VERSION 5.7 ;
  NOWIREEXTENSIONATPIN ON ;
  DIVIDERCHAR "/" ;
  BUSBITCHARS "[]" ;
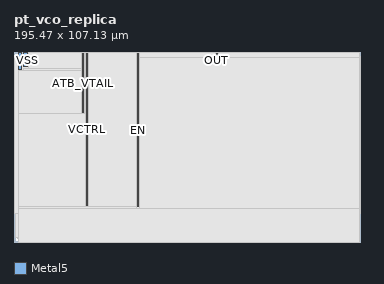
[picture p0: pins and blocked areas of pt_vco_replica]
MACRO pt_vco_replica
  CLASS BLOCK ;
  FOREIGN pt_vco_replica ;
  ORIGIN -1.500 0.000 ;
  SIZE 195.470 BY 107.130 ;
  PIN EN
    ANTENNAGATEAREA 2.240000 ;
    PORT
      LAYER Metal5 ;
        RECT 71.180 19.760 71.620 106.350 ;
    END
  END EN
  PIN VCTRL
    ANTENNAGATEAREA 65.000000 ;
    ANTENNADIFFAREA 0.440000 ;
    PORT
      LAYER Metal5 ;
        RECT 42.380 20.480 42.820 106.350 ;
    END
  END VCTRL
  PIN OUT
    ANTENNADIFFAREA 2.640000 ;
    PORT
      LAYER Metal5 ;
        RECT 115.580 104.750 116.020 106.350 ;
    END
  END OUT
  PIN ATB_VTAIL
    ANTENNADIFFAREA 46.799999 ;
    PORT
      LAYER Metal5 ;
        RECT 39.980 72.800 40.420 106.350 ;
    END
  END ATB_VTAIL
  PIN VDD
    USE POWER ;
    PORT
      LAYER Metal5 ;
        RECT 4.000 97.370 6.000 107.130 ;
    END
  END VDD
  PIN VSS
    USE GROUND ;
    PORT
      LAYER Metal5 ;
        RECT 7.000 98.690 9.000 107.130 ;
    END
  END VSS
  OBS
      LAYER Nwell ;
        RECT 3.450 2.000 166.820 96.430 ;
      LAYER Metal1 ;
        RECT 3.750 2.185 181.710 95.830 ;
      LAYER Metal2 ;
        RECT 2.250 2.780 196.220 95.730 ;
      LAYER Metal3 ;
        RECT 2.250 2.780 196.220 104.810 ;
      LAYER Metal4 ;
        RECT 1.500 16.060 196.970 104.810 ;
      LAYER Metal5 ;
        RECT 9.600 106.950 196.420 107.130 ;
        RECT 9.600 98.090 39.380 106.950 ;
        RECT 6.600 96.770 39.380 98.090 ;
        RECT 4.000 72.200 39.380 96.770 ;
        RECT 41.020 72.200 41.780 106.950 ;
        RECT 4.000 19.880 41.780 72.200 ;
        RECT 43.420 19.880 70.580 106.950 ;
        RECT 4.000 19.160 70.580 19.880 ;
        RECT 72.220 104.150 114.980 106.950 ;
        RECT 116.620 104.150 196.420 106.950 ;
        RECT 72.220 19.160 196.420 104.150 ;
        RECT 4.000 0.000 196.420 19.160 ;
  END
END pt_vco_replica
END LIBRARY

